VERSION 5.7 ;
  NOWIREEXTENSIONATPIN ON ;
  DIVIDERCHAR "/" ;
  BUSBITCHARS "[]" ;
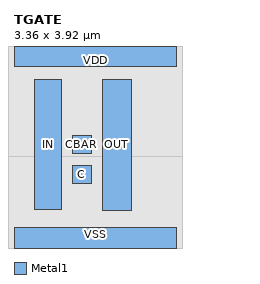
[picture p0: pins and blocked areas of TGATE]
MACRO TGATE
  CLASS CORE ;
  FOREIGN TGATE ;
  ORIGIN 0.000 0.000 ;
  SIZE 3.360 BY 3.920 ;
  SYMMETRY X Y ;
  SITE GF018hv5v_mcu_sc7 ;
  PIN VDD
    DIRECTION INOUT ;
    USE POWER ;
    PORT
      LAYER Metal1 ;
        RECT 0.000 3.620 3.360 4.220 ;
    END
  END VDD
  PIN VSS
    DIRECTION INOUT ;
    USE GROUND ;
    PORT
      LAYER Metal1 ;
        RECT 0.000 -0.300 3.360 0.300 ;
    END
  END VSS
  PIN IN
    DIRECTION INOUT ;
    USE SIGNAL ;
    ANTENNADIFFAREA 1.713600 ;
    PORT
      LAYER Metal1 ;
        RECT 0.430 0.670 0.980 3.350 ;
    END
  END IN
  PIN OUT
    DIRECTION INOUT ;
    USE SIGNAL ;
    ANTENNADIFFAREA 1.795400 ;
    PORT
      LAYER Metal1 ;
        RECT 1.820 0.660 2.420 3.350 ;
    END
  END OUT
  PIN C
    DIRECTION INPUT ;
    USE SIGNAL ;
    ANTENNAGATEAREA 0.339000 ;
    PORT
      LAYER Metal1 ;
        RECT 1.210 1.200 1.590 1.580 ;
    END
  END C
  PIN CBAR
    DIRECTION INPUT ;
    USE SIGNAL ;
    ANTENNAGATEAREA 0.732000 ;
    PORT
      LAYER Metal1 ;
        RECT 1.210 1.820 1.590 2.200 ;
    END
  END CBAR
  OBS
      LAYER Nwell ;
        RECT -0.430 1.760 3.790 4.350 ;
      LAYER Pwell ;
        RECT -0.430 -0.430 3.790 1.760 ;
  END
END TGATE
END LIBRARY

